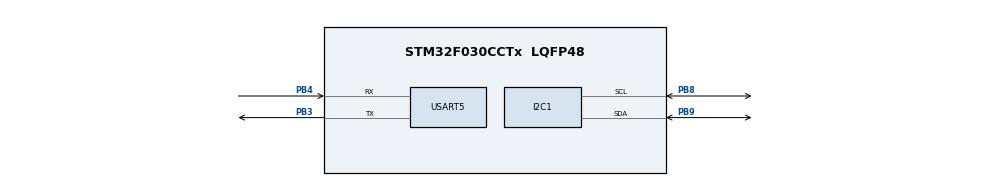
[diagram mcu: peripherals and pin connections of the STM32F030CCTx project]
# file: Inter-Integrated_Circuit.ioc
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Mcu.Family=STM32F0
Mcu.Name=STM32F030CCTx
Mcu.Package=LQFP48
PB3.Mode=Asynchronous
PB3.Signal=USART5_TX
PB4.Mode=Asynchronous
PB4.Signal=USART5_RX
PB8.Mode=I2C
PB8.Signal=I2C1_SCL
PB9.Mode=I2C
PB9.Signal=I2C1_SDA
ProjectManager.HeapSize=0x200
ProjectManager.StackSize=0x400
ProjectManager.TargetToolchain=CMake
USART5.VirtualMode-Asynchronous=VM_ASYNC
board=custom

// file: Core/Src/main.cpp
/* USER CODE BEGIN Header */
/**
  ******************************************************************************
  * @file           : main.c
  * @brief          : Main program body
  ******************************************************************************
  * @attention
  *
  * Copyright (c) 2024 STMicroelectronics.
  * All rights reserved.
  *
  * This software is licensed under terms that can be found in the LICENSE file
  * in the root directory of this software component.
  * If no LICENSE file comes with this software, it is provided AS-IS.
  *
  ******************************************************************************
  */
/* USER CODE END Header */
#include "main.h"
#include <cstdint>
#include <cstdio>
#include <cstdlib>
#include <vector>

#include "accelerometer.h"
#include "barometer.h"
#include "factory.h"
#include "LPS331AP_LPS25H.h"
#include "LSM303D.h"
#include "uart_helper.h"

I2C_HandleTypeDef hi2c1;

UART_HandleTypeDef huart5;

void SystemClock_Config(void);
static void MX_GPIO_Init(void);
static void MX_I2C1_Init(void);
static void MX_USART5_UART_Init(void);

int main(void)
{

    /* MCU Configuration--------------------------------------------------------*/

    /* Reset of all peripherals, Initializes the Flash interface and the Systick. */
    HAL_Init();

    /* Configure the system clock */
    SystemClock_Config();

    /* Initialize all configured peripherals */
    MX_GPIO_Init();
    MX_I2C1_Init();
    MX_USART5_UART_Init();
    /* USER CODE BEGIN 2 */

    barometer* myBarometer = factory::getBarometer();
    accelerometer* myAccelerometer = factory::getAccelerometer();
    magnetometer* myMagnetometer = factory::getMagnetometer();

    while (1)
    {
        uint32_t num_measurements = uart_read_num();
        uint32_t additional_delay = uart_read_num();

        uart_write_id("Barometer", myBarometer->readWHO_AM_I());
        uart_write_id("Accelerometer", myAccelerometer->readWHO_AM_I());
        uart_write_id("Magnetometer", myMagnetometer->readWHO_AM_I());

        uart_write_header();
        uint32_t measurement_start_ms = HAL_GetTick(); // the start of the measurements in ms

        double temperature, pressure, magnet_x, magnet_y, magnet_z, acc_x, acc_y, acc_z;
        for (uint32_t i = 0; i < num_measurements; i++)
        {
            // get all measurements
            myBarometer->read_barometer(temperature, pressure);
            myAccelerometer->read_accelerometer(acc_x, acc_y, acc_z);
            myMagnetometer->read_magnetometer(magnet_x, magnet_y, magnet_z);
            double current_s = ((double) HAL_GetTick() - measurement_start_ms) / 1000; // current time since measurement_start_ms in s

            uart_write_data(&current_s, &temperature, &pressure, &magnet_x, &magnet_y, &magnet_z, &acc_x, &acc_y, &acc_z);

            if (additional_delay > 0)
                HAL_Delay(additional_delay);
        }
        uart_goodbye();
    }

    delete myBarometer;
    delete myAccelerometer;
    delete myMagnetometer;

    /* USER CODE END 2 */

    /* Infinite loop */
    while (1)
    {
    }
}

void SystemClock_Config(void)
{
    RCC_OscInitTypeDef RCC_OscInitStruct = {0};
    RCC_ClkInitTypeDef RCC_ClkInitStruct = {0};
    RCC_PeriphCLKInitTypeDef PeriphClkInit = {0};

    /** Initializes the RCC Oscillators according to the specified parameters
    * in the RCC_OscInitTypeDef structure.
    */
    RCC_OscInitStruct.OscillatorType = RCC_OSCILLATORTYPE_HSI;
    RCC_OscInitStruct.HSIState = RCC_HSI_ON;
    RCC_OscInitStruct.HSICalibrationValue = RCC_HSICALIBRATION_DEFAULT;
    RCC_OscInitStruct.PLL.PLLState = RCC_PLL_ON;
    RCC_OscInitStruct.PLL.PLLSource = RCC_PLLSOURCE_HSI;
    RCC_OscInitStruct.PLL.PLLMUL = RCC_PLL_MUL6;
    RCC_OscInitStruct.PLL.PREDIV = RCC_PREDIV_DIV1;
    if (HAL_RCC_OscConfig(&RCC_OscInitStruct) != HAL_OK)
    {
        Error_Handler();
    }

    /** Initializes the CPU, AHB and APB buses clocks
    */
    RCC_ClkInitStruct.ClockType = RCC_CLOCKTYPE_HCLK | RCC_CLOCKTYPE_SYSCLK
        | RCC_CLOCKTYPE_PCLK1;
    RCC_ClkInitStruct.SYSCLKSource = RCC_SYSCLKSOURCE_PLLCLK;
    RCC_ClkInitStruct.AHBCLKDivider = RCC_SYSCLK_DIV1;
    RCC_ClkInitStruct.APB1CLKDivider = RCC_HCLK_DIV1;

    if (HAL_RCC_ClockConfig(&RCC_ClkInitStruct, FLASH_LATENCY_1) != HAL_OK)
    {
        Error_Handler();
    }
    PeriphClkInit.PeriphClockSelection = RCC_PERIPHCLK_I2C1;
    PeriphClkInit.I2c1ClockSelection = RCC_I2C1CLKSOURCE_HSI;
    if (HAL_RCCEx_PeriphCLKConfig(&PeriphClkInit) != HAL_OK)
    {
        Error_Handler();
    }
}

static void MX_I2C1_Init(void)
{

    hi2c1.Instance = I2C1;
    hi2c1.Init.Timing = 0x2000090E;
    hi2c1.Init.OwnAddress1 = 0;
    hi2c1.Init.AddressingMode = I2C_ADDRESSINGMODE_7BIT;
    hi2c1.Init.DualAddressMode = I2C_DUALADDRESS_DISABLE;
    hi2c1.Init.OwnAddress2 = 0;
    hi2c1.Init.OwnAddress2Masks = I2C_OA2_NOMASK;
    hi2c1.Init.GeneralCallMode = I2C_GENERALCALL_DISABLE;
    hi2c1.Init.NoStretchMode = I2C_NOSTRETCH_DISABLE;
    if (HAL_I2C_Init(&hi2c1) != HAL_OK)
    {
        Error_Handler();
    }

    /** Configure Analogue filter
    */
    if (HAL_I2CEx_ConfigAnalogFilter(&hi2c1, I2C_ANALOGFILTER_ENABLE) != HAL_OK)
    {
        Error_Handler();
    }

    /** Configure Digital filter
    */
    if (HAL_I2CEx_ConfigDigitalFilter(&hi2c1, 0) != HAL_OK)
    {
        Error_Handler();
    }
}

static void MX_USART5_UART_Init(void)
{

    huart5.Instance = USART5;
    huart5.Init.BaudRate = 115200;
    huart5.Init.WordLength = UART_WORDLENGTH_8B;
    huart5.Init.StopBits = UART_STOPBITS_1;
    huart5.Init.Parity = UART_PARITY_NONE;
    huart5.Init.Mode = UART_MODE_TX_RX;
    huart5.Init.HwFlowCtl = UART_HWCONTROL_NONE;
    huart5.Init.OverSampling = UART_OVERSAMPLING_16;
    huart5.Init.OneBitSampling = UART_ONE_BIT_SAMPLE_DISABLE;
    huart5.AdvancedInit.AdvFeatureInit = UART_ADVFEATURE_NO_INIT;
    if (HAL_UART_Init(&huart5) != HAL_OK)
    {
        Error_Handler();
    }
}

static void MX_GPIO_Init(void)
{

    /* GPIO Ports Clock Enable */
    __HAL_RCC_GPIOF_CLK_ENABLE();
    __HAL_RCC_GPIOB_CLK_ENABLE();

}

void Error_Handler(void)
{
    __disable_irq();
    while (1)
    {
    }
}
